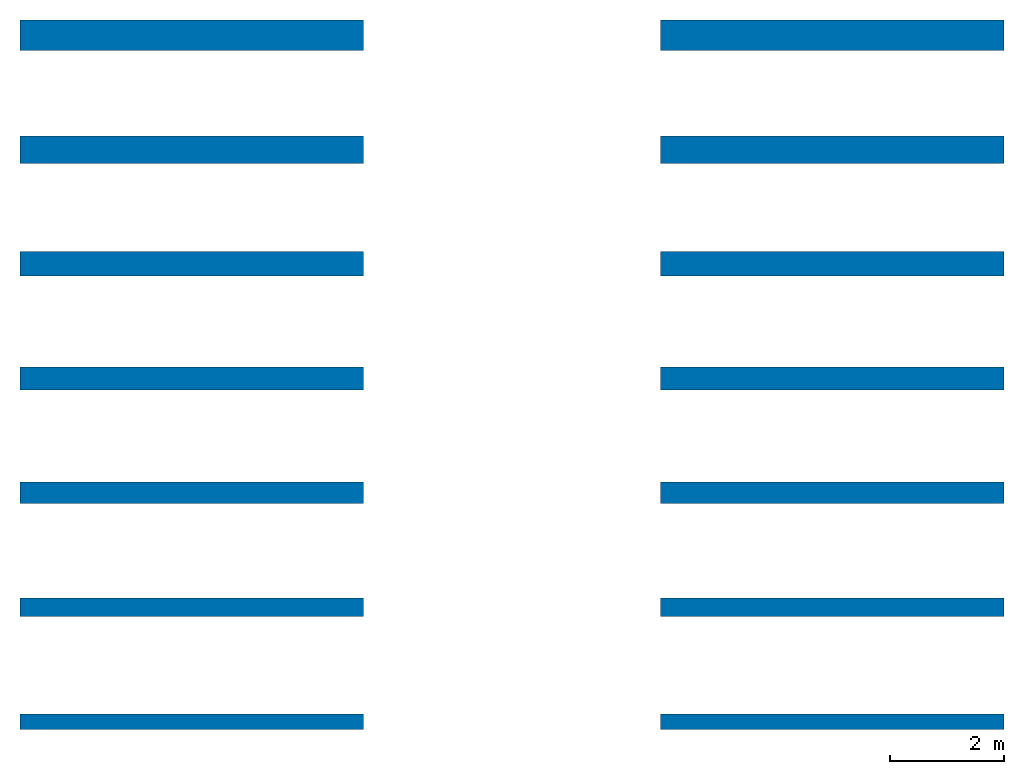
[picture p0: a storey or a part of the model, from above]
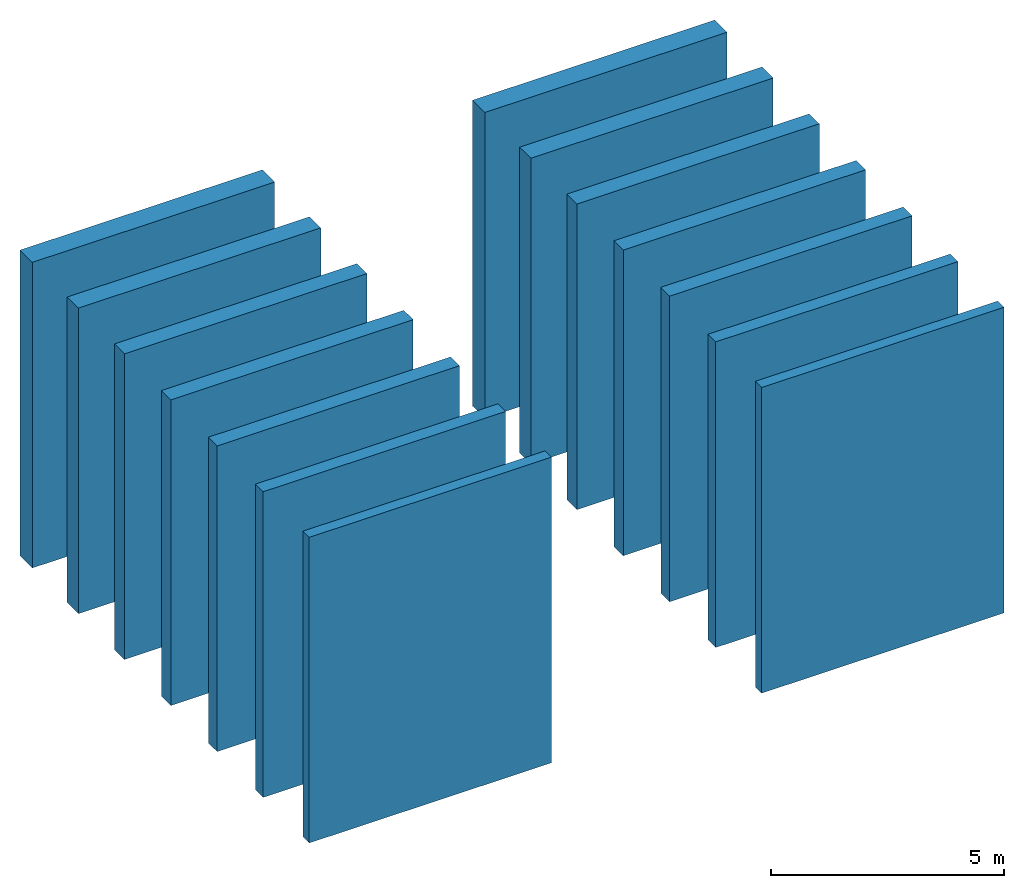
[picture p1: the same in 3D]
Properties of the parts of a building model (IFC2X3)

# File
Description: ViewDefinition [CoordinationView]
File name: Numero
Time: 2019-05-03T09:52:24
Written by: The EXPRESS Data Manager Version 5.02.0100.07 : 28 Aug 2013
Made in: 20150220_1215(x64) - Exporter 16.0.428.0 - Default UI
Comment: STEP Physical File produced by: The EXPRESS Data Manager Version 5.02.0100.07 : 28 Aug 2013 * Module: EDMstepFileFactory/EDMstandAlone * Creation date: Fri May 03 09:52:24 2019 * Host: HP-RS * Database: C:\Users\EKORU_~1\AppData\Local\Temp\{D1C3EE5B-D62B-4305-A047-E3DBEC2418A1}\ifc * Database version: 5507 * Database creation date: Fri May 03 09:52:23 2019 * Schema: IFC2X3 * Model: DataRepository.ifc * Model creation date: Fri May 03 09:52:24 2019 * Header model: DataRepository.ifc_HeaderModel * Header model creation date: Fri May 03 09:52:24 2019 * EDMuser: sdai-user * EDMgroup: sdai-group * License ID and type: 5605 : Permanent license. Expiry date: * EDMstepFileFactory options: 020000

# IfcProject, Numero
LongName: Nome; Phase: Stato

# IfcSite, Default
RefLatitude: 41, 47, 59, 999999; RefLongitude: 12, 35, 59, 999999; RefElevation: 0 mm
Altro - Categoria: Informazioni sul progetto; Data di consegna del progetto: Data; Indirizzo del progetto: Immettere l'indirizzo; Nome del cliente: Proprietario; Nome del progetto: Nome; Numero del progetto: Numero; Stato del progetto: Stato

# IfcBuilding
Pset_BuildingCommon - NumberOfStoreys: 1
Altro - Categoria: Informazioni sul progetto; Data di consegna del progetto: Data; Indirizzo del progetto: Immettere l'indirizzo; Nome del cliente: Proprietario; Nome del progetto: Nome; Numero del progetto: Numero; Stato del progetto: Stato

# IfcBuildingStorey, Livello 1
LongName: Livello 1; Elevation: 0 mm
Vincoli - Base quota altimetrica: Punto base progetto; Quota altimetrica: 0 mm
Altro - Categoria: Livelli; Famiglia: Livello: Estremità 8 mm; Famiglia e tipo: Livello: Estremità 8 mm; ID tipo: Livello: Estremità 8 mm; Tipo: Livello: Estremità 8 mm; Nome famiglia: Livello
Dati identità - Strutturale: no; Nome: Livello 1; Piano edificio: yes; Nome del tipo: Estremità 8 mm
Dimensioni - Altezza di calcolo: 0 mm
Grafica - Colore: 0; Modello di linea: Centro; Simbolo: Estremità del livello - Cerchio: Estremità del livello - Cerchio; Simbolo a estremità 1 per default: no; Simbolo a estremità 2 per default: yes; Spessore di linea: 1

# IfcWallStandardCase: Muro di base:Sistema GASBETON Energy sp. 269 per tamponatura, Muro di base:Sistema GASBETON Energy sp. 269 per tamponatura:139188
In: Livello 1
Type - PredefinedType: STANDARD; Material: tonachino colorato ai silicati/silossani di finitura 2 mm, GASBETON Multiraso esterni 5 mm, GASBETON Multicem 15 mm, GASBETON Energy 240 mm, GASBETON Incollarasa 5 mm, GASBETON Multiraso interni 2 mm
Type - Altro - Categoria: Muri; Nome famiglia: Muro di base
Type - Costruzione - Funzione: Esterno; Ripiegatura agli inserti: Non ripiegare; Ripiegatura alle estremità: Nessuno; Larghezza: 269 mm
Type - Dati identità - Descrizione: Parete rifinita formata dalla seguente stratigrafia (dall'esterno verso l'interno): tonachino colorato ai silicati/silossani, Multiraso esterni, rete da intonaco GASBETON, Multicem, blocchi GASBETON Energy, Incollarasa, rete da intonaco GASBETON, Multira; Installation Guide: http://www.gasbeton.it/wp-content/uploads/2017/11/GASBETON-Guida-alla-progettazione.pdf; Modello: Soluzione muratura esterna Gasbeton Energy; Nome del tipo: Sistema GASBETON Energy sp. 269 per tamponatura; Product data url: www.gasbeton.it; Produttore: EKORU s.r.l.; Resistenza al fuoco: EI 240; Euroclasse A1; Techinical data sheet: http://www.gasbeton.it/download/; URL: http://www.ekoru.it/; Youtube channel: https://www.youtube.com/user/bacchispa
Type - Generale - Edition number: 1; Manufacturer country: Italy; Manufacturer name: EKORU s.r.l.; Product family: walls
Type - Grafica - Colore del retino a dettaglio basso: 0
Type - Materiali e finiture - Materiale strutturale: GASBETON Energy; Material main: Autoclaved Aerated Concrete (AAC)
Type - Proprietà analitiche - Ruvidità: 2; Assorbimento: 0.7; Coefficiente di scambio termico (U): 0.0956416; Massa termica: 470200; Resistenza termica (R): 10.4557
Altro - Famiglia: Muro di base: Sistema GASBETON Energy sp. 269 per tamponatura; Famiglia e tipo: Muro di base: Sistema GASBETON Energy sp. 269 per tamponatura; ID tipo: Muro di base: Sistema GASBETON Energy sp. 269 per tamponatura; Tipo: Muro di base: Sistema GASBETON Energy sp. 269 per tamponatura
Dimensioni - Area: 48 m2; Lunghezza: 6000 mm; Volume: 12.912 m3
Fasi - Fase di creazione: Fase 1
Strutturale - Attiva modello analitico: no; Strutturale: no; Utilizzo strutturale: Non portante
Vincoli - Delimita il locale: yes; Distanza estensione base: 0 mm; Distanza estensione superiore: 0 mm; La base è associata: no; La parte superiore è associata: no; Linea di ubicazione: Linea d'asse del muro; Offset base: 0 mm; Offset superiore: 0 mm; Relativo a massa: no; Vincolo di base: Livello: Livello 1; Altezza non collegata: 8000 mm
Pset_WallCommon - LoadBearing: no; ExtendToStructure: no; IsExternal: yes; Reference: Sistema GASBETON Energy sp. 269 per tamponatura; FireRating: EI 240; Euroclasse A1; ThermalTransmittance: 0.0956416 kg/K/s3
Pset_ManufacturerTypeInformation - Manufacturer: EKORU s.r.l.

# IfcWallStandardCase: Muro di base:Sistema GASBETON Energy sp. 329 per tamponatura, Muro di base:Sistema GASBETON Energy sp. 329 per tamponatura:139180
In: Livello 1
Type - PredefinedType: STANDARD; Material: tonachino colorato ai silicati/silossani di finitura 2 mm, GASBETON Multiraso esterni 5 mm, GASBETON Multicem 15 mm, GASBETON Energy 300 mm, GASBETON Incollarasa 5 mm, GASBETON Multiraso interni 2 mm
Type - Altro - Categoria: Muri; Nome famiglia: Muro di base
Type - Costruzione - Funzione: Esterno; Ripiegatura agli inserti: Non ripiegare; Ripiegatura alle estremità: Nessuno; Larghezza: 329 mm
Type - Dati identità - Descrizione: Parete rifinita formata dalla seguente stratigrafia (dall'esterno verso l'interno): tonachino colorato ai silicati/silossani, Multiraso esterni, rete da intonaco GASBETON, Multicem, blocchi GASBETON Energy, Incollarasa, rete da intonaco GASBETON, Multira; Installation Guide: http://www.gasbeton.it/wp-content/uploads/2017/11/GASBETON-Guida-alla-progettazione.pdf; Modello: Soluzione muratura esterna Gasbeton Energy; Nome del tipo: Sistema GASBETON Energy sp. 329 per tamponatura; Product data url: www.gasbeton.it; Produttore: EKORU s.r.l.; Resistenza al fuoco: EI 240; Euroclasse A1; Techinical data sheet: http://www.gasbeton.it/download/; URL: http://www.ekoru.it/; Youtube channel: https://www.youtube.com/user/bacchispa
Type - Generale - Edition number: 1; Manufacturer country: Italy; Manufacturer name: EKORU s.r.l.; Product family: walls
Type - Grafica - Colore del retino a dettaglio basso: 0
Type - Materiali e finiture - Materiale strutturale: GASBETON Energy; Material main: Autoclaved Aerated Concrete (AAC)
Type - Proprietà analitiche - Ruvidità: 2; Assorbimento: 0.7; Coefficiente di scambio termico (U): 0.0766422; Massa termica: 580814; Resistenza termica (R): 13.0476
Altro - Famiglia: Muro di base: Sistema GASBETON Energy sp. 329 per tamponatura; Famiglia e tipo: Muro di base: Sistema GASBETON Energy sp. 329 per tamponatura; ID tipo: Muro di base: Sistema GASBETON Energy sp. 329 per tamponatura; Tipo: Muro di base: Sistema GASBETON Energy sp. 329 per tamponatura
Dimensioni - Area: 48 m2; Lunghezza: 6000 mm; Volume: 15.792 m3
Fasi - Fase di creazione: Fase 1
Strutturale - Attiva modello analitico: no; Strutturale: no; Utilizzo strutturale: Non portante
Vincoli - Delimita il locale: yes; Distanza estensione base: 0 mm; Distanza estensione superiore: 0 mm; La base è associata: no; La parte superiore è associata: no; Linea di ubicazione: Linea d'asse del muro; Offset base: 0 mm; Offset superiore: 0 mm; Relativo a massa: no; Vincolo di base: Livello: Livello 1; Altezza non collegata: 8000 mm
Pset_WallCommon - LoadBearing: no; ExtendToStructure: no; IsExternal: yes; Reference: Sistema GASBETON Energy sp. 329 per tamponatura; FireRating: EI 240; Euroclasse A1; ThermalTransmittance: 0.0766422 kg/K/s3
Pset_ManufacturerTypeInformation - Manufacturer: EKORU s.r.l.

# IfcWallStandardCase: Muro di base:Sistema GASBETON Energy sp. 379 per tamponatura, Muro di base:Sistema GASBETON Energy sp. 379 per tamponatura:139172
In: Livello 1
Type - PredefinedType: STANDARD; Material: tonachino colorato ai silicati/silossani di finitura 2 mm, GASBETON Multiraso esterni 5 mm, GASBETON Multicem 15 mm, GASBETON Energy 350 mm, GASBETON Incollarasa 5 mm, GASBETON Multiraso interni 2 mm
Type - Altro - Categoria: Muri; Nome famiglia: Muro di base
Type - Costruzione - Funzione: Esterno; Ripiegatura agli inserti: Non ripiegare; Ripiegatura alle estremità: Nessuno; Larghezza: 379 mm
Type - Dati identità - Descrizione: Parete rifinita formata dalla seguente stratigrafia (dall'esterno verso l'interno): tonachino colorato ai silicati/silossani, Multiraso esterni, rete da intonaco GASBETON, Multicem, blocchi GASBETON Energy, Incollarasa, rete da intonaco GASBETON, Multira; Installation Guide: http://www.gasbeton.it/wp-content/uploads/2017/11/GASBETON-Guida-alla-progettazione.pdf; Modello: Soluzione muratura esterna Gasbeton Energy; Nome del tipo: Sistema GASBETON Energy sp. 379 per tamponatura; Product data url: www.gasbeton.it; Produttore: EKORU s.r.l.; Resistenza al fuoco: EI 240; Euroclasse A1; Techinical data sheet: http://www.gasbeton.it/download/; URL: http://www.ekoru.it/; Youtube channel: https://www.youtube.com/user/bacchispa
Type - Generale - Edition number: 1; Manufacturer country: Italy; Manufacturer name: EKORU s.r.l.; Product family: walls
Type - Grafica - Colore del retino a dettaglio basso: 0
Type - Materiali e finiture - Materiale strutturale: GASBETON Energy; Material main: Autoclaved Aerated Concrete (AAC)
Type - Proprietà analitiche - Ruvidità: 2; Assorbimento: 0.7; Coefficiente di scambio termico (U): 0.0657566; Massa termica: 672993; Resistenza termica (R): 15.2076
Altro - Famiglia: Muro di base: Sistema GASBETON Energy sp. 379 per tamponatura; Famiglia e tipo: Muro di base: Sistema GASBETON Energy sp. 379 per tamponatura; ID tipo: Muro di base: Sistema GASBETON Energy sp. 379 per tamponatura; Tipo: Muro di base: Sistema GASBETON Energy sp. 379 per tamponatura
Dimensioni - Area: 48 m2; Lunghezza: 6000 mm; Volume: 18.192 m3
Fasi - Fase di creazione: Fase 1
Strutturale - Attiva modello analitico: no; Strutturale: no; Utilizzo strutturale: Non portante
Vincoli - Delimita il locale: yes; Distanza estensione base: 0 mm; Distanza estensione superiore: 0 mm; La base è associata: no; La parte superiore è associata: no; Linea di ubicazione: Linea d'asse del muro; Offset base: 0 mm; Offset superiore: 0 mm; Relativo a massa: no; Vincolo di base: Livello: Livello 1; Altezza non collegata: 8000 mm
Pset_WallCommon - LoadBearing: no; ExtendToStructure: no; IsExternal: yes; Reference: Sistema GASBETON Energy sp. 379 per tamponatura; FireRating: EI 240; Euroclasse A1; ThermalTransmittance: 0.0657566 kg/K/s3
Pset_ManufacturerTypeInformation - Manufacturer: EKORU s.r.l.

# IfcWallStandardCase: Muro di base:Sistema GASBETON Energy sp. 404 per tamponatura, Muro di base:Sistema GASBETON Energy sp. 404 per tamponatura:139164
In: Livello 1
Type - PredefinedType: STANDARD; Material: tonachino colorato ai silicati/silossani di finitura 2 mm, GASBETON Multiraso esterni 5 mm, GASBETON Multicem 15 mm, GASBETON Energy 375 mm, GASBETON Incollarasa 5 mm, GASBETON Multiraso interni 2 mm
Type - Altro - Categoria: Muri; Nome famiglia: Muro di base
Type - Costruzione - Funzione: Esterno; Ripiegatura agli inserti: Non ripiegare; Ripiegatura alle estremità: Nessuno; Larghezza: 404 mm
Type - Dati identità - Descrizione: Parete rifinita formata dalla seguente stratigrafia (dall'esterno verso l'interno): tonachino colorato ai silicati/silossani, Multiraso esterni, rete da intonaco GASBETON, Multicem, blocchi GASBETON Energy, Incollarasa, rete da intonaco GASBETON, Multira; Installation Guide: http://www.gasbeton.it/wp-content/uploads/2017/11/GASBETON-Guida-alla-progettazione.pdf; Modello: Soluzione muratura esterna Gasbeton Energy; Nome del tipo: Sistema GASBETON Energy sp. 404 per tamponatura; Product data url: www.gasbeton.it; Produttore: EKORU s.r.l.; Resistenza al fuoco: EI 240; Euroclasse A1; Techinical data sheet: http://www.gasbeton.it/download/; URL: http://www.ekoru.it/; Youtube channel: https://www.youtube.com/user/bacchispa
Type - Generale - Edition number: 1; Manufacturer country: Italy; Manufacturer name: EKORU s.r.l.; Product family: walls
Type - Grafica - Colore del retino a dettaglio basso: 0
Type - Materiali e finiture - Materiale strutturale: GASBETON Energy; Material main: Autoclaved Aerated Concrete (AAC)
Type - Proprietà analitiche - Ruvidità: 2; Assorbimento: 0.7; Coefficiente di scambio termico (U): 0.0613965; Massa termica: 719082; Resistenza termica (R): 16.2876
Altro - Famiglia: Muro di base: Sistema GASBETON Energy sp. 404 per tamponatura; Famiglia e tipo: Muro di base: Sistema GASBETON Energy sp. 404 per tamponatura; ID tipo: Muro di base: Sistema GASBETON Energy sp. 404 per tamponatura; Tipo: Muro di base: Sistema GASBETON Energy sp. 404 per tamponatura
Dimensioni - Area: 48 m2; Lunghezza: 6000 mm; Volume: 19.392 m3
Fasi - Fase di creazione: Fase 1
Strutturale - Attiva modello analitico: no; Strutturale: no; Utilizzo strutturale: Non portante
Vincoli - Delimita il locale: yes; Distanza estensione base: 0 mm; Distanza estensione superiore: 0 mm; La base è associata: no; La parte superiore è associata: no; Linea di ubicazione: Linea d'asse del muro; Offset base: 0 mm; Offset superiore: 0 mm; Relativo a massa: no; Vincolo di base: Livello: Livello 1; Altezza non collegata: 8000 mm
Pset_WallCommon - LoadBearing: no; ExtendToStructure: no; IsExternal: yes; Reference: Sistema GASBETON Energy sp. 404 per tamponatura; FireRating: EI 240; Euroclasse A1; ThermalTransmittance: 0.0613965 kg/K/s3
Pset_ManufacturerTypeInformation - Manufacturer: EKORU s.r.l.

# IfcWallStandardCase: Muro di base:Sistema GASBETON Energy sp. 429 per tamponatura, Muro di base:Sistema GASBETON Energy sp. 429 per tamponatura:139156
In: Livello 1
Type - PredefinedType: STANDARD; Material: tonachino colorato ai silicati/silossani di finitura 2 mm, GASBETON Multiraso esterni 5 mm, GASBETON Multicem 15 mm, GASBETON Energy 400 mm, GASBETON Incollarasa 5 mm, GASBETON Multiraso interni 2 mm
Type - Altro - Categoria: Muri; Nome famiglia: Muro di base
Type - Costruzione - Funzione: Esterno; Ripiegatura agli inserti: Non ripiegare; Ripiegatura alle estremità: Nessuno; Larghezza: 429 mm
Type - Dati identità - Descrizione: Parete rifinita formata dalla seguente stratigrafia (dall'esterno verso l'interno): tonachino colorato ai silicati/silossani, Multiraso esterni, rete da intonaco GASBETON, Multicem, blocchi GASBETON Energy, Incollarasa, rete da intonaco GASBETON, Multira; Installation Guide: http://www.gasbeton.it/wp-content/uploads/2017/11/GASBETON-Guida-alla-progettazione.pdf; Modello: Soluzione muratura esterna Gasbeton Energy; Nome del tipo: Sistema GASBETON Energy sp. 429 per tamponatura; Product data url: www.gasbeton.it; Produttore: EKORU s.r.l.; Resistenza al fuoco: EI 240; Euroclasse A1; Techinical data sheet: http://www.gasbeton.it/download/; URL: http://www.ekoru.it/; Youtube channel: https://www.youtube.com/user/bacchispa
Type - Generale - Edition number: 1; Manufacturer country: Italy; Manufacturer name: EKORU s.r.l.; Product family: walls
Type - Grafica - Colore del retino a dettaglio basso: 0
Type - Materiali e finiture - Materiale strutturale: GASBETON Energy; Material main: Autoclaved Aerated Concrete (AAC)
Type - Proprietà analitiche - Ruvidità: 2; Assorbimento: 0.7; Coefficiente di scambio termico (U): 0.0575786; Massa termica: 765171; Resistenza termica (R): 17.3676
Altro - Famiglia: Muro di base: Sistema GASBETON Energy sp. 429 per tamponatura; Famiglia e tipo: Muro di base: Sistema GASBETON Energy sp. 429 per tamponatura; ID tipo: Muro di base: Sistema GASBETON Energy sp. 429 per tamponatura; Tipo: Muro di base: Sistema GASBETON Energy sp. 429 per tamponatura
Dimensioni - Area: 48 m2; Lunghezza: 6000 mm; Volume: 20.592 m3
Fasi - Fase di creazione: Fase 1
Strutturale - Attiva modello analitico: no; Strutturale: no; Utilizzo strutturale: Non portante
Vincoli - Delimita il locale: yes; Distanza estensione base: 0 mm; Distanza estensione superiore: 0 mm; La base è associata: no; La parte superiore è associata: no; Linea di ubicazione: Linea d'asse del muro; Offset base: 0 mm; Offset superiore: 0 mm; Relativo a massa: no; Vincolo di base: Livello: Livello 1; Altezza non collegata: 8000 mm
Pset_WallCommon - LoadBearing: no; ExtendToStructure: no; IsExternal: yes; Reference: Sistema GASBETON Energy sp. 429 per tamponatura; FireRating: EI 240; Euroclasse A1; ThermalTransmittance: 0.0575786 kg/K/s3
Pset_ManufacturerTypeInformation - Manufacturer: EKORU s.r.l.

# IfcWallStandardCase: Muro di base:Sistema GASBETON Energy sp. 479 per tamponatura, Muro di base:Sistema GASBETON Energy sp. 479 per tamponatura:139148
In: Livello 1
Type - PredefinedType: STANDARD; Material: tonachino colorato ai silicati/silossani di finitura 2 mm, GASBETON Multiraso esterni 5 mm, GASBETON Multicem 15 mm, GASBETON Energy 450 mm, GASBETON Incollarasa 5 mm, GASBETON Multiraso interni 2 mm
Type - Altro - Categoria: Muri; Nome famiglia: Muro di base
Type - Costruzione - Funzione: Esterno; Ripiegatura agli inserti: Non ripiegare; Ripiegatura alle estremità: Nessuno; Larghezza: 479 mm
Type - Dati identità - Descrizione: Parete rifinita formata dalla seguente stratigrafia (dall'esterno verso l'interno): tonachino colorato ai silicati/silossani, Multiraso esterni, rete da intonaco GASBETON, Multicem, blocchi GASBETON Energy, Incollarasa, rete da intonaco GASBETON, Multira; Installation Guide: http://www.gasbeton.it/wp-content/uploads/2017/11/GASBETON-Guida-alla-progettazione.pdf; Modello: Soluzione muratura esterna Gasbeton Energy; Nome del tipo: Sistema GASBETON Energy sp. 479 per tamponatura; Product data url: www.gasbeton.it; Produttore: EKORU s.r.l.; Resistenza al fuoco: EI 240; Euroclasse A1; Techinical data sheet: http://www.gasbeton.it/download/; URL: http://www.ekoru.it/; Youtube channel: https://www.youtube.com/user/bacchispa
Type - Generale - Edition number: 1; Manufacturer country: Italy; Manufacturer name: EKORU s.r.l.; Product family: walls
Type - Grafica - Colore del retino a dettaglio basso: 0
Type - Materiali e finiture - Materiale strutturale: GASBETON Energy; Material main: Autoclaved Aerated Concrete (AAC)
Type - Proprietà analitiche - Ruvidità: 2; Assorbimento: 0.7; Coefficiente di scambio termico (U): 0.0512098; Massa termica: 857350; Resistenza termica (R): 19.5275
Altro - Famiglia: Muro di base: Sistema GASBETON Energy sp. 479 per tamponatura; Famiglia e tipo: Muro di base: Sistema GASBETON Energy sp. 479 per tamponatura; ID tipo: Muro di base: Sistema GASBETON Energy sp. 479 per tamponatura; Tipo: Muro di base: Sistema GASBETON Energy sp. 479 per tamponatura
Dimensioni - Area: 48 m2; Lunghezza: 6000 mm; Volume: 22.992 m3
Fasi - Fase di creazione: Fase 1
Strutturale - Attiva modello analitico: no; Strutturale: no; Utilizzo strutturale: Non portante
Vincoli - Delimita il locale: yes; Distanza estensione base: 0 mm; Distanza estensione superiore: 0 mm; La base è associata: no; La parte superiore è associata: no; Linea di ubicazione: Linea d'asse del muro; Offset base: 0 mm; Offset superiore: 0 mm; Relativo a massa: no; Vincolo di base: Livello: Livello 1; Altezza non collegata: 8000 mm
Pset_WallCommon - LoadBearing: no; ExtendToStructure: no; IsExternal: yes; Reference: Sistema GASBETON Energy sp. 479 per tamponatura; FireRating: EI 240; Euroclasse A1; ThermalTransmittance: 0.0512098 kg/K/s3
Pset_ManufacturerTypeInformation - Manufacturer: EKORU s.r.l.

# IfcWallStandardCase: Muro di base:Sistema GASBETON Energy+ IDRO sp. 269 per tamponatura, Muro di base:Sistema GASBETON Energy+ IDRO sp. 269 per tamponatura:139192
In: Livello 1
Type - PredefinedType: STANDARD; Material: tonachino colorato ai silicati/silossani di finitura 2 mm, GASBETON Multiraso esterni 5 mm, GASBETON Multicem 15 mm, GASBETON Energy 240 mm, GASBETON Incollarasa 5 mm, GASBETON Multiraso interni 2 mm
Type - Altro - Categoria: Muri; Nome famiglia: Muro di base
Type - Costruzione - Funzione: Esterno; Ripiegatura agli inserti: Non ripiegare; Ripiegatura alle estremità: Nessuno; Larghezza: 269 mm
Type - Dati identità - Descrizione: Parete rifinita formata dalla seguente stratigrafia (dall'esterno verso l'interno): tonachino colorato ai silicati/silossani, Multiraso esterni, rete da intonaco GASBETON, Multicem, blocchi GASBETON Energy, Incollarasa, rete da intonaco GASBETON, Multira; Installation Guide: http://www.gasbeton.it/wp-content/uploads/2017/11/GASBETON-Guida-alla-progettazione.pdf; Modello: Soluzione muratura esterna Gasbeton Energy con primo corso idrofobizzato; Nome del tipo: Sistema GASBETON Energy+ IDRO sp. 269 per tamponatura; Product data url: www.gasbeton.it; Produttore: EKORU s.r.l.; Resistenza al fuoco: EI 240; Euroclasse A1; Techinical data sheet: http://www.gasbeton.it/download/; URL: http://www.ekoru.it/; Youtube channel: https://www.youtube.com/user/bacchispa
Type - Generale - Edition number: 1; Manufacturer country: Italy; Manufacturer name: EKORU s.r.l.; Product family: walls
Type - Grafica - Colore del retino a dettaglio basso: 0
Type - Materiali e finiture - Materiale strutturale: GASBETON Energy; Material main: Autoclaved Aerated Concrete (AAC)
Type - Proprietà analitiche - Ruvidità: 2; Assorbimento: 0.7; Coefficiente di scambio termico (U): 0.080541; Massa termica: 666040; Resistenza termica (R): 12.416
Altro - Famiglia: Muro di base: Sistema GASBETON Energy+ IDRO sp. 269 per tamponatura; Famiglia e tipo: Muro di base: Sistema GASBETON Energy+ IDRO sp. 269 per tamponatura; ID tipo: Muro di base: Sistema GASBETON Energy+ IDRO sp. 269 per tamponatura; Tipo: Muro di base: Sistema GASBETON Energy+ IDRO sp. 269 per tamponatura
Dimensioni - Area: 48 m2; Lunghezza: 6000 mm; Volume: 12.912 m3
Fasi - Fase di creazione: Fase 1
Strutturale - Attiva modello analitico: no; Strutturale: no; Utilizzo strutturale: Non portante
Vincoli - Delimita il locale: yes; Distanza estensione base: 0 mm; Distanza estensione superiore: 0 mm; La base è associata: no; La parte superiore è associata: no; Linea di ubicazione: Linea d'asse del muro; Offset base: 0 mm; Offset superiore: 0 mm; Relativo a massa: no; Vincolo di base: Livello: Livello 1; Altezza non collegata: 8000 mm
Pset_WallCommon - LoadBearing: no; ExtendToStructure: no; IsExternal: yes; Reference: Sistema GASBETON Energy+ IDRO sp. 269 per tamponatura; FireRating: EI 240; Euroclasse A1; ThermalTransmittance: 0.080541 kg/K/s3
Pset_ManufacturerTypeInformation - Manufacturer: EKORU s.r.l.

# IfcWallStandardCase: Muro di base:Sistema GASBETON Energy+ IDRO sp. 329 per tamponatura, Muro di base:Sistema GASBETON Energy+ IDRO sp. 329 per tamponatura:153701
In: Livello 1
Type - PredefinedType: STANDARD; Material: tonachino colorato ai silicati/silossani di finitura 2 mm, GASBETON Multiraso esterni 5 mm, GASBETON Multicem 15 mm, GASBETON Energy 300 mm, GASBETON Incollarasa 5 mm, GASBETON Multiraso interni 2 mm
Type - Altro - Categoria: Muri; Nome famiglia: Muro di base
Type - Costruzione - Funzione: Esterno; Ripiegatura agli inserti: Non ripiegare; Ripiegatura alle estremità: Nessuno; Larghezza: 329 mm
Type - Dati identità - Descrizione: Parete rifinita formata dalla seguente stratigrafia (dall'esterno verso l'interno): tonachino colorato ai silicati/silossani, Multiraso esterni, rete da intonaco GASBETON, Multicem, blocchi GASBETON Energy, Incollarasa, rete da intonaco GASBETON, Multira; Installation Guide: http://www.gasbeton.it/wp-content/uploads/2017/11/GASBETON-Guida-alla-progettazione.pdf; Modello: Soluzione muratura esterna Gasbeton Energy con primo corso idrofobizzato; Nome del tipo: Sistema GASBETON Energy+ IDRO sp. 329 per tamponatura; Product data url: www.gasbeton.it; Produttore: EKORU s.r.l.; Resistenza al fuoco: EI 240; Euroclasse A1; Techinical data sheet: http://www.gasbeton.it/download/; URL: http://www.ekoru.it/; Youtube channel: https://www.youtube.com/user/bacchispa
Type - Generale - Edition number: 1; Manufacturer country: Italy; Manufacturer name: EKORU s.r.l.; Product family: walls
Type - Grafica - Colore del retino a dettaglio basso: 0
Type - Materiali e finiture - Materiale strutturale: GASBETON Energy; Material main: Autoclaved Aerated Concrete (AAC)
Type - Proprietà analitiche - Ruvidità: 2; Assorbimento: 0.7; Coefficiente di scambio termico (U): 0.0645242; Massa termica: 825614; Resistenza termica (R): 15.4981
Altro - Famiglia: Muro di base: Sistema GASBETON Energy+ IDRO sp. 329 per tamponatura; Famiglia e tipo: Muro di base: Sistema GASBETON Energy+ IDRO sp. 329 per tamponatura; ID tipo: Muro di base: Sistema GASBETON Energy+ IDRO sp. 329 per tamponatura; Tipo: Muro di base: Sistema GASBETON Energy+ IDRO sp. 329 per tamponatura
Dimensioni - Area: 48 m2; Lunghezza: 6000 mm; Volume: 15.792 m3
Fasi - Fase di creazione: Fase 1
Strutturale - Attiva modello analitico: no; Strutturale: no; Utilizzo strutturale: Non portante
Vincoli - Delimita il locale: yes; Distanza estensione base: 0 mm; Distanza estensione superiore: 0 mm; La base è associata: no; La parte superiore è associata: no; Linea di ubicazione: Linea d'asse del muro; Offset base: 0 mm; Offset superiore: 0 mm; Relativo a massa: no; Vincolo di base: Livello: Livello 1; Altezza non collegata: 8000 mm
Pset_WallCommon - LoadBearing: no; ExtendToStructure: no; IsExternal: yes; Reference: Sistema GASBETON Energy+ IDRO sp. 329 per tamponatura; FireRating: EI 240; Euroclasse A1; ThermalTransmittance: 0.0645242 kg/K/s3
Pset_ManufacturerTypeInformation - Manufacturer: EKORU s.r.l.

# IfcWallStandardCase: Muro di base:Sistema GASBETON Energy+ IDRO sp. 379 per tamponatura, Muro di base:Sistema GASBETON Energy+ IDRO sp. 379 per tamponatura:153700
In: Livello 1
Type - PredefinedType: STANDARD; Material: tonachino colorato ai silicati/silossani di finitura 2 mm, GASBETON Multiraso esterni 5 mm, GASBETON Multicem 15 mm, GASBETON Energy 350 mm, GASBETON Incollarasa 5 mm, GASBETON Multiraso interni 2 mm
Type - Altro - Categoria: Muri; Nome famiglia: Muro di base
Type - Costruzione - Funzione: Esterno; Ripiegatura agli inserti: Non ripiegare; Ripiegatura alle estremità: Nessuno; Larghezza: 379 mm
Type - Dati identità - Descrizione: Parete rifinita formata dalla seguente stratigrafia (dall'esterno verso l'interno): tonachino colorato ai silicati/silossani, Multiraso esterni, rete da intonaco GASBETON, Multicem, blocchi GASBETON Energy, Incollarasa, rete da intonaco GASBETON, Multira; Installation Guide: http://www.gasbeton.it/wp-content/uploads/2017/11/GASBETON-Guida-alla-progettazione.pdf; Modello: Soluzione muratura esterna Gasbeton Energy con primo corso idrofobizzato; Nome del tipo: Sistema GASBETON Energy+ IDRO sp. 379 per tamponatura; Product data url: www.gasbeton.it; Produttore: EKORU s.r.l.; Resistenza al fuoco: EI 240; Euroclasse A1; Techinical data sheet: http://www.gasbeton.it/download/; URL: http://www.ekoru.it/; Youtube channel: https://www.youtube.com/user/bacchispa
Type - Generale - Edition number: 1; Manufacturer country: Italy; Manufacturer name: EKORU s.r.l.; Product family: walls
Type - Grafica - Colore del retino a dettaglio basso: 0
Type - Materiali e finiture - Materiale strutturale: GASBETON Energy; Material main: Autoclaved Aerated Concrete (AAC)
Type - Proprietà analitiche - Ruvidità: 2; Assorbimento: 0.7; Coefficiente di scambio termico (U): 0.0553513; Massa termica: 958593; Resistenza termica (R): 18.0664
Altro - Famiglia: Muro di base: Sistema GASBETON Energy+ IDRO sp. 379 per tamponatura; Famiglia e tipo: Muro di base: Sistema GASBETON Energy+ IDRO sp. 379 per tamponatura; ID tipo: Muro di base: Sistema GASBETON Energy+ IDRO sp. 379 per tamponatura; Tipo: Muro di base: Sistema GASBETON Energy+ IDRO sp. 379 per tamponatura
Dimensioni - Area: 48 m2; Lunghezza: 6000 mm; Volume: 18.192 m3
Fasi - Fase di creazione: Fase 1
Strutturale - Attiva modello analitico: no; Strutturale: no; Utilizzo strutturale: Non portante
Vincoli - Delimita il locale: yes; Distanza estensione base: 0 mm; Distanza estensione superiore: 0 mm; La base è associata: no; La parte superiore è associata: no; Linea di ubicazione: Linea d'asse del muro; Offset base: 0 mm; Offset superiore: 0 mm; Relativo a massa: no; Vincolo di base: Livello: Livello 1; Altezza non collegata: 8000 mm
Pset_WallCommon - LoadBearing: no; ExtendToStructure: no; IsExternal: yes; Reference: Sistema GASBETON Energy+ IDRO sp. 379 per tamponatura; FireRating: EI 240; Euroclasse A1; ThermalTransmittance: 0.0553513 kg/K/s3
Pset_ManufacturerTypeInformation - Manufacturer: EKORU s.r.l.

# IfcWallStandardCase: Muro di base:Sistema GASBETON Energy+ IDRO sp. 404 per tamponatura, Muro di base:Sistema GASBETON Energy+ IDRO sp. 404 per tamponatura:153699
In: Livello 1
Type - PredefinedType: STANDARD; Material: tonachino colorato ai silicati/silossani di finitura 2 mm, GASBETON Multiraso esterni 5 mm, GASBETON Multicem 15 mm, GASBETON Energy 375 mm, GASBETON Incollarasa 5 mm, GASBETON Multiraso interni 2 mm
Type - Altro - Categoria: Muri; Nome famiglia: Muro di base
Type - Costruzione - Funzione: Esterno; Ripiegatura agli inserti: Non ripiegare; Ripiegatura alle estremità: Nessuno; Larghezza: 404 mm
Type - Dati identità - Descrizione: Parete rifinita formata dalla seguente stratigrafia (dall'esterno verso l'interno): tonachino colorato ai silicati/silossani, Multiraso esterni, rete da intonaco GASBETON, Multicem, blocchi GASBETON Energy, Incollarasa, rete da intonaco GASBETON, Multira; Installation Guide: http://www.gasbeton.it/wp-content/uploads/2017/11/GASBETON-Guida-alla-progettazione.pdf; Modello: Soluzione muratura esterna Gasbeton Energy con primo corso idrofobizzato; Nome del tipo: Sistema GASBETON Energy+ IDRO sp. 404 per tamponatura; Product data url: www.gasbeton.it; Produttore: EKORU s.r.l.; Resistenza al fuoco: EI 240; Euroclasse A1; Techinical data sheet: http://www.gasbeton.it/download/; URL: http://www.ekoru.it/; Youtube channel: https://www.youtube.com/user/bacchispa
Type - Generale - Edition number: 1; Manufacturer country: Italy; Manufacturer name: EKORU s.r.l.; Product family: walls
Type - Grafica - Colore del retino a dettaglio basso: 0
Type - Materiali e finiture - Materiale strutturale: GASBETON Energy; Material main: Autoclaved Aerated Concrete (AAC)
Type - Proprietà analitiche - Ruvidità: 2; Assorbimento: 0.7; Coefficiente di scambio termico (U): 0.051678; Massa termica: 1025082; Resistenza termica (R): 19.3506
Altro - Famiglia: Muro di base: Sistema GASBETON Energy+ IDRO sp. 404 per tamponatura; Famiglia e tipo: Muro di base: Sistema GASBETON Energy+ IDRO sp. 404 per tamponatura; ID tipo: Muro di base: Sistema GASBETON Energy+ IDRO sp. 404 per tamponatura; Tipo: Muro di base: Sistema GASBETON Energy+ IDRO sp. 404 per tamponatura
Dimensioni - Area: 48 m2; Lunghezza: 6000 mm; Volume: 19.392 m3
Fasi - Fase di creazione: Fase 1
Strutturale - Attiva modello analitico: no; Strutturale: no; Utilizzo strutturale: Non portante
Vincoli - Delimita il locale: yes; Distanza estensione base: 0 mm; Distanza estensione superiore: 0 mm; La base è associata: no; La parte superiore è associata: no; Linea di ubicazione: Linea d'asse del muro; Offset base: 0 mm; Offset superiore: 0 mm; Relativo a massa: no; Vincolo di base: Livello: Livello 1; Altezza non collegata: 8000 mm
Pset_WallCommon - LoadBearing: no; ExtendToStructure: no; IsExternal: yes; Reference: Sistema GASBETON Energy+ IDRO sp. 404 per tamponatura; FireRating: EI 240; Euroclasse A1; ThermalTransmittance: 0.051678 kg/K/s3
Pset_ManufacturerTypeInformation - Manufacturer: EKORU s.r.l.

# IfcWallStandardCase: Muro di base:Sistema GASBETON Energy+ IDRO sp. 429 per tamponatura, Muro di base:Sistema GASBETON Energy+ IDRO sp. 429 per tamponatura:153698
In: Livello 1
Type - PredefinedType: STANDARD; Material: tonachino colorato ai silicati/silossani di finitura 2 mm, GASBETON Multiraso esterni 5 mm, GASBETON Multicem 15 mm, GASBETON Energy 400 mm, GASBETON Incollarasa 5 mm, GASBETON Multiraso interni 2 mm
Type - Altro - Categoria: Muri; Nome famiglia: Muro di base
Type - Costruzione - Funzione: Esterno; Ripiegatura agli inserti: Non ripiegare; Ripiegatura alle estremità: Nessuno; Larghezza: 429 mm
Type - Dati identità - Descrizione: Parete rifinita formata dalla seguente stratigrafia (dall'esterno verso l'interno): tonachino colorato ai silicati/silossani, Multiraso esterni, rete da intonaco GASBETON, Multicem, blocchi GASBETON Energy, Incollarasa, rete da intonaco GASBETON, Multira; Installation Guide: http://www.gasbeton.it/wp-content/uploads/2017/11/GASBETON-Guida-alla-progettazione.pdf; Modello: Soluzione muratura esterna Gasbeton Energy con primo corso idrofobizzato; Nome del tipo: Sistema GASBETON Energy+ IDRO sp. 429 per tamponatura; Product data url: www.gasbeton.it; Produttore: EKORU s.r.l.; Resistenza al fuoco: EI 240; Euroclasse A1; Techinical data sheet: http://www.gasbeton.it/download/; URL: http://www.ekoru.it/; Youtube channel: https://www.youtube.com/user/bacchispa
Type - Generale - Edition number: 1; Manufacturer country: Italy; Manufacturer name: EKORU s.r.l.; Product family: walls
Type - Grafica - Colore del retino a dettaglio basso: 0
Type - Materiali e finiture - Materiale strutturale: GASBETON Energy; Material main: Autoclaved Aerated Concrete (AAC)
Type - Proprietà analitiche - Ruvidità: 2; Assorbimento: 0.7; Coefficiente di scambio termico (U): 0.0484619; Massa termica: 1091571; Resistenza termica (R): 20.6348
Altro - Famiglia: Muro di base: Sistema GASBETON Energy+ IDRO sp. 429 per tamponatura; Famiglia e tipo: Muro di base: Sistema GASBETON Energy+ IDRO sp. 429 per tamponatura; ID tipo: Muro di base: Sistema GASBETON Energy+ IDRO sp. 429 per tamponatura; Tipo: Muro di base: Sistema GASBETON Energy+ IDRO sp. 429 per tamponatura
Dimensioni - Area: 48 m2; Lunghezza: 6000 mm; Volume: 20.592 m3
Fasi - Fase di creazione: Fase 1
Strutturale - Attiva modello analitico: no; Strutturale: no; Utilizzo strutturale: Non portante
Vincoli - Delimita il locale: yes; Distanza estensione base: 0 mm; Distanza estensione superiore: 0 mm; La base è associata: no; La parte superiore è associata: no; Linea di ubicazione: Linea d'asse del muro; Offset base: 0 mm; Offset superiore: 0 mm; Relativo a massa: no; Vincolo di base: Livello: Livello 1; Altezza non collegata: 8000 mm
Pset_WallCommon - LoadBearing: no; ExtendToStructure: no; IsExternal: yes; Reference: Sistema GASBETON Energy+ IDRO sp. 429 per tamponatura; FireRating: EI 240; Euroclasse A1; ThermalTransmittance: 0.0484619 kg/K/s3
Pset_ManufacturerTypeInformation - Manufacturer: EKORU s.r.l.

# IfcWallStandardCase: Muro di base:Sistema GASBETON Energy+ IDRO sp. 479 per tamponatura, Muro di base:Sistema GASBETON Energy+ IDRO sp. 479 per tamponatura:153697
In: Livello 1
Type - PredefinedType: STANDARD; Material: tonachino colorato ai silicati/silossani di finitura 2 mm, GASBETON Multiraso esterni 5 mm, GASBETON Multicem 15 mm, GASBETON Energy 450 mm, GASBETON Incollarasa 5 mm, GASBETON Multiraso interni 2 mm
Type - Altro - Categoria: Muri; Nome famiglia: Muro di base
Type - Costruzione - Funzione: Esterno; Ripiegatura agli inserti: Non ripiegare; Ripiegatura alle estremità: Nessuno; Larghezza: 479 mm
Type - Dati identità - Descrizione: Parete rifinita formata dalla seguente stratigrafia (dall'esterno verso l'interno): tonachino colorato ai silicati/silossani, Multiraso esterni, rete da intonaco GASBETON, Multicem, blocchi GASBETON Energy, Incollarasa, rete da intonaco GASBETON, Multira; Installation Guide: http://www.gasbeton.it/wp-content/uploads/2017/11/GASBETON-Guida-alla-progettazione.pdf; Modello: Soluzione muratura esterna Gasbeton Energy con primo corso idrofobizzato; Nome del tipo: Sistema GASBETON Energy+ IDRO sp. 479 per tamponatura; Product data url: www.gasbeton.it; Produttore: EKORU s.r.l.; Resistenza al fuoco: EI 240; Euroclasse A1; Techinical data sheet: http://www.gasbeton.it/download/; URL: http://www.ekoru.it/; Youtube channel: https://www.youtube.com/user/bacchispa
Type - Generale - Edition number: 1; Manufacturer country: Italy; Manufacturer name: EKORU s.r.l.; Product family: walls
Type - Grafica - Colore del retino a dettaglio basso: 0
Type - Materiali e finiture - Materiale strutturale: GASBETON Energy; Material main: Autoclaved Aerated Concrete (AAC)
Type - Proprietà analitiche - Ruvidità: 2; Assorbimento: 0.7; Coefficiente di scambio termico (U): 0.0430976; Massa termica: 1224550; Resistenza termica (R): 23.2031
Altro - Famiglia: Muro di base: Sistema GASBETON Energy+ IDRO sp. 479 per tamponatura; Famiglia e tipo: Muro di base: Sistema GASBETON Energy+ IDRO sp. 479 per tamponatura; ID tipo: Muro di base: Sistema GASBETON Energy+ IDRO sp. 479 per tamponatura; Tipo: Muro di base: Sistema GASBETON Energy+ IDRO sp. 479 per tamponatura
Dimensioni - Area: 48 m2; Lunghezza: 6000 mm; Volume: 22.992 m3
Fasi - Fase di creazione: Fase 1
Strutturale - Attiva modello analitico: no; Strutturale: no; Utilizzo strutturale: Non portante
Vincoli - Delimita il locale: yes; Distanza estensione base: 0 mm; Distanza estensione superiore: 0 mm; La base è associata: no; La parte superiore è associata: no; Linea di ubicazione: Linea d'asse del muro; Offset base: 0 mm; Offset superiore: 0 mm; Relativo a massa: no; Vincolo di base: Livello: Livello 1; Altezza non collegata: 8000 mm
Pset_WallCommon - LoadBearing: no; ExtendToStructure: no; IsExternal: yes; Reference: Sistema GASBETON Energy+ IDRO sp. 479 per tamponatura; FireRating: EI 240; Euroclasse A1; ThermalTransmittance: 0.0430976 kg/K/s3
Pset_ManufacturerTypeInformation - Manufacturer: EKORU s.r.l.

# IfcWallStandardCase: Muro di base:Sistema GASBETON Energy+ IDRO sp. 529 per tamponatura (2)
In: Livello 1
Type - PredefinedType: STANDARD; Material: tonachino colorato ai silicati/silossani di finitura 2 mm, GASBETON Multiraso esterni 5 mm, GASBETON Multicem 15 mm, GASBETON Energy 500 mm, GASBETON Incollarasa 5 mm, GASBETON Multiraso interni 2 mm
Type - Altro - Categoria: Muri; Nome famiglia: Muro di base
Type - Costruzione - Funzione: Esterno; Larghezza: 529 mm; Ripiegatura agli inserti: Non ripiegare; Ripiegatura alle estremità: Nessuno
Type - Dati identità - Descrizione: Parete rifinita formata dalla seguente stratigrafia (dall'esterno verso l'interno): tonachino colorato ai silicati/silossani, Multiraso esterni, rete da intonaco GASBETON, Multicem, blocchi GASBETON Energy, Incollarasa, rete da intonaco GASBETON, Multira; Installation Guide: http://www.gasbeton.it/wp-content/uploads/2017/11/GASBETON-Guida-alla-progettazione.pdf; Modello: Soluzione muratura esterna Gasbeton Energy con primo corso idrofobizzato; Nome del tipo: Sistema GASBETON Energy+ IDRO sp. 529 per tamponatura; Product data url: www.gasbeton.it; Produttore: EKORU s.r.l.; Resistenza al fuoco: EI 240; Euroclasse A1; Techinical data sheet: http://www.gasbeton.it/download/; URL: http://www.ekoru.it/; Youtube channel: https://www.youtube.com/user/bacchispa
Type - Generale - Edition number: 1; Manufacturer country: Italy; Manufacturer name: EKORU s.r.l.; Product family: walls
Type - Grafica - Colore del retino a dettaglio basso: 0
Type - Materiali e finiture - Materiale strutturale: GASBETON Energy; Material main: Autoclaved Aerated Concrete (AAC)
Type - Proprietà analitiche - Assorbimento: 0.7; Coefficiente di scambio termico (U): 0.0388026; Massa termica: 1357528; Resistenza termica (R): 25.7715; Ruvidità: 2
Altro - Famiglia: Muro di base: Sistema GASBETON Energy+ IDRO sp. 529 per tamponatura; Famiglia e tipo: Muro di base: Sistema GASBETON Energy+ IDRO sp. 529 per tamponatura; ID tipo: Muro di base: Sistema GASBETON Energy+ IDRO sp. 529 per tamponatura; Tipo: Muro di base: Sistema GASBETON Energy+ IDRO sp. 529 per tamponatura
Dimensioni - Area: 48 m2; Lunghezza: 6000 mm; Volume: 25.392 m3
Fasi - Fase di creazione: Fase 1
Strutturale - Attiva modello analitico: no; Strutturale: no; Utilizzo strutturale: Non portante
Vincoli - Altezza non collegata: 8000 mm; Delimita il locale: yes; Distanza estensione base: 0 mm; Distanza estensione superiore: 0 mm; La base è associata: no; La parte superiore è associata: no; Linea di ubicazione: Linea d'asse del muro; Offset base: 0 mm; Offset superiore: 0 mm; Relativo a massa: no; Vincolo di base: Livello: Livello 1
Pset_WallCommon - Reference: Sistema GASBETON Energy+ IDRO sp. 529 per tamponatura; LoadBearing: no; ExtendToStructure: no; IsExternal: yes; FireRating: EI 240; Euroclasse A1; ThermalTransmittance: 0.0388026 kg/K/s3
Pset_ManufacturerTypeInformation - Manufacturer: EKORU s.r.l.
Name (Muro di base:Sistema GASBETON Energy+ IDRO sp. 529 per tamponatura:...)
138935
153696
